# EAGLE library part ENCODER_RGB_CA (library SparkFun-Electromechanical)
Illuminated Rotary Encoder w/ RGB LED and select switch EC12PLRGBSDVBF-D: http://top-up.so-buy.com/front/bin/ptdetail.phtml?Part=EC12PLRGBSDVBF-D

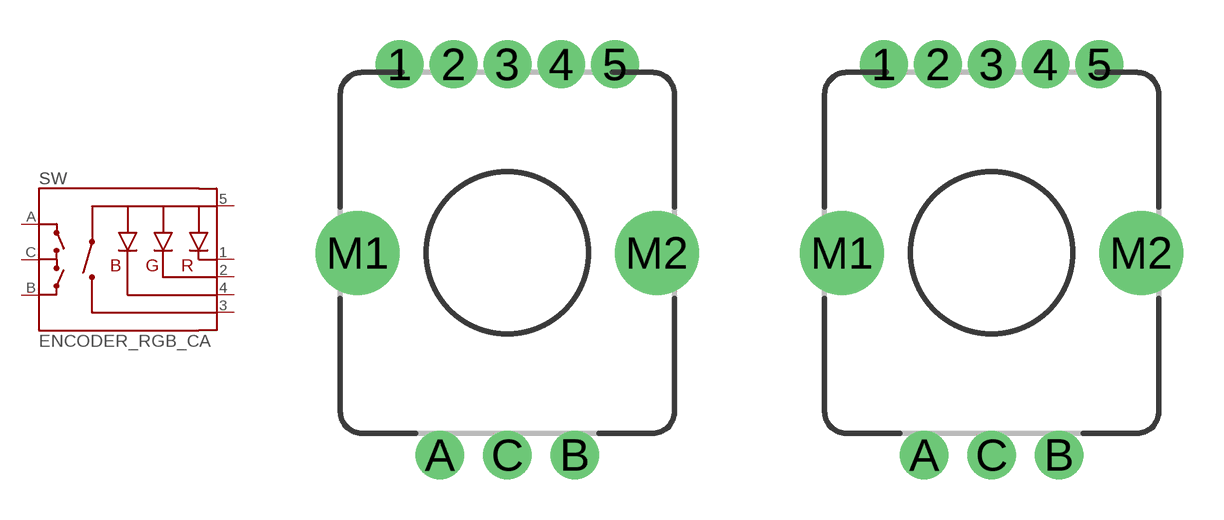
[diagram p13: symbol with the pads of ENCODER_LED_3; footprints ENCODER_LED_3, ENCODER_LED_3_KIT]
Designator prefix SW

## ENCODER_RGB_CA  [ENCODER_LED_3]
1  -R  pas
2  -G  pas
3  SW  pas
4  -B  pas
5  +  pas
A  A
B  B
C  C

## ENCODER_RGB_CAKIT  [ENCODER_LED_3_KIT]
Pads as for ENCODER_LED_3

## Footprint ENCODER_LED_3 (pad centres in mm)
drill 1.1 pad 1.778: 1 -4,7; 2 -2,7; 3 0,7; 4 2,7; 5 4,7
drill 1.1 pad 1.8: A -2.5,-7.5; B 2.5,-7.5; C 0,-7.5
drill 2.1: M1 -5.55,0; M2 5.55,0

## Footprint ENCODER_LED_3_KIT (pad centres in mm)
drill 1.1 pad 1.778: 1 -4,7; 2 -2,7; 3 0,7; 4 2,7; 5 4,7
drill 1.1 pad 1.8: A -2.5,-7.5; B 2.5,-7.5; C 0,-7.5
drill 2.1: M1 -5.55,0; M2 5.55,0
